# Generated by FakeRAM 2.0
VERSION 5.7 ;
BUSBITCHARS "[]" ;
PROPERTYDEFINITIONS
  MACRO width INTEGER ;
  MACRO depth INTEGER ;
  MACRO banks INTEGER ;
END PROPERTYDEFINITIONS
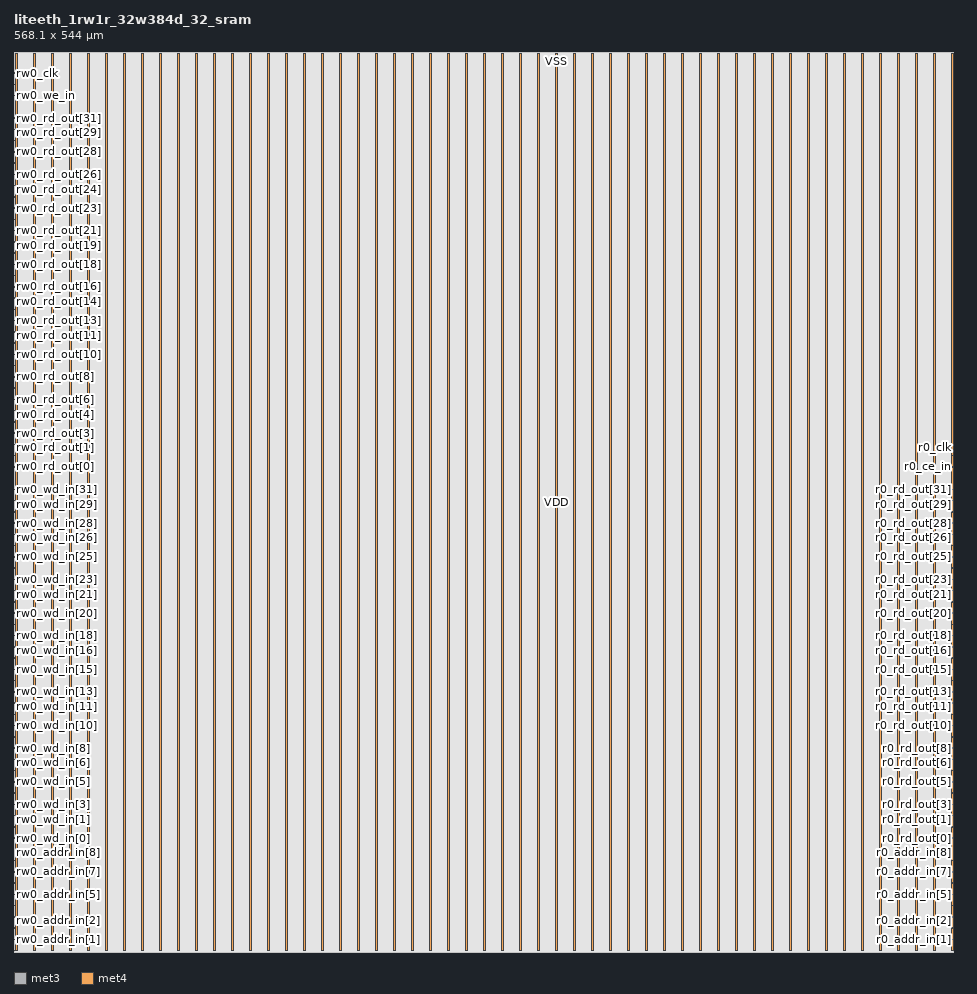
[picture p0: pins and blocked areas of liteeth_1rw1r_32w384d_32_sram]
MACRO liteeth_1rw1r_32w384d_32_sram
  PROPERTY width 32 ;
  PROPERTY depth 384 ;
  PROPERTY banks 1 ;
  FOREIGN liteeth_1rw1r_32w384d_32_sram 0 0 ;
  SYMMETRY X Y R90 ;
  SIZE 568.100 BY 544.000 ;
  CLASS BLOCK ;
  PIN r0_addr_in[0]
    DIRECTION INPUT ;
    USE SIGNAL ;
    SHAPE ABUTMENT ;
    PORT
      LAYER met3 ;
      RECT 567.300 0.680 568.100 0.980 ;
    END
  END r0_addr_in[0]
  PIN r0_addr_in[1]
    DIRECTION INPUT ;
    USE SIGNAL ;
    SHAPE ABUTMENT ;
    PORT
      LAYER met3 ;
      RECT 567.300 7.480 568.100 7.780 ;
    END
  END r0_addr_in[1]
  PIN r0_addr_in[2]
    DIRECTION INPUT ;
    USE SIGNAL ;
    SHAPE ABUTMENT ;
    PORT
      LAYER met3 ;
      RECT 567.300 14.280 568.100 14.580 ;
    END
  END r0_addr_in[2]
  PIN r0_addr_in[3]
    DIRECTION INPUT ;
    USE SIGNAL ;
    SHAPE ABUTMENT ;
    PORT
      LAYER met3 ;
      RECT 567.300 21.080 568.100 21.380 ;
    END
  END r0_addr_in[3]
  PIN r0_addr_in[4]
    DIRECTION INPUT ;
    USE SIGNAL ;
    SHAPE ABUTMENT ;
    PORT
      LAYER met3 ;
      RECT 567.300 27.880 568.100 28.180 ;
    END
  END r0_addr_in[4]
  PIN r0_addr_in[5]
    DIRECTION INPUT ;
    USE SIGNAL ;
    SHAPE ABUTMENT ;
    PORT
      LAYER met3 ;
      RECT 567.300 34.680 568.100 34.980 ;
    END
  END r0_addr_in[5]
  PIN r0_addr_in[6]
    DIRECTION INPUT ;
    USE SIGNAL ;
    SHAPE ABUTMENT ;
    PORT
      LAYER met3 ;
      RECT 567.300 41.480 568.100 41.780 ;
    END
  END r0_addr_in[6]
  PIN r0_addr_in[7]
    DIRECTION INPUT ;
    USE SIGNAL ;
    SHAPE ABUTMENT ;
    PORT
      LAYER met3 ;
      RECT 567.300 48.280 568.100 48.580 ;
    END
  END r0_addr_in[7]
  PIN r0_addr_in[8]
    DIRECTION INPUT ;
    USE SIGNAL ;
    SHAPE ABUTMENT ;
    PORT
      LAYER met3 ;
      RECT 567.300 55.080 568.100 55.380 ;
    END
  END r0_addr_in[8]
  PIN r0_rd_out[0]
    DIRECTION OUTPUT ;
    USE SIGNAL ;
    SHAPE ABUTMENT ;
    PORT
      LAYER met3 ;
      RECT 567.300 68.680 568.100 68.980 ;
    END
  END r0_rd_out[0]
  PIN r0_rd_out[1]
    DIRECTION OUTPUT ;
    USE SIGNAL ;
    SHAPE ABUTMENT ;
    PORT
      LAYER met3 ;
      RECT 567.300 75.480 568.100 75.780 ;
    END
  END r0_rd_out[1]
  PIN r0_rd_out[2]
    DIRECTION OUTPUT ;
    USE SIGNAL ;
    SHAPE ABUTMENT ;
    PORT
      LAYER met3 ;
      RECT 567.300 82.280 568.100 82.580 ;
    END
  END r0_rd_out[2]
  PIN r0_rd_out[3]
    DIRECTION OUTPUT ;
    USE SIGNAL ;
    SHAPE ABUTMENT ;
    PORT
      LAYER met3 ;
      RECT 567.300 89.080 568.100 89.380 ;
    END
  END r0_rd_out[3]
  PIN r0_rd_out[4]
    DIRECTION OUTPUT ;
    USE SIGNAL ;
    SHAPE ABUTMENT ;
    PORT
      LAYER met3 ;
      RECT 567.300 95.880 568.100 96.180 ;
    END
  END r0_rd_out[4]
  PIN r0_rd_out[5]
    DIRECTION OUTPUT ;
    USE SIGNAL ;
    SHAPE ABUTMENT ;
    PORT
      LAYER met3 ;
      RECT 567.300 102.680 568.100 102.980 ;
    END
  END r0_rd_out[5]
  PIN r0_rd_out[6]
    DIRECTION OUTPUT ;
    USE SIGNAL ;
    SHAPE ABUTMENT ;
    PORT
      LAYER met3 ;
      RECT 567.300 109.480 568.100 109.780 ;
    END
  END r0_rd_out[6]
  PIN r0_rd_out[7]
    DIRECTION OUTPUT ;
    USE SIGNAL ;
    SHAPE ABUTMENT ;
    PORT
      LAYER met3 ;
      RECT 567.300 116.280 568.100 116.580 ;
    END
  END r0_rd_out[7]
  PIN r0_rd_out[8]
    DIRECTION OUTPUT ;
    USE SIGNAL ;
    SHAPE ABUTMENT ;
    PORT
      LAYER met3 ;
      RECT 567.300 123.080 568.100 123.380 ;
    END
  END r0_rd_out[8]
  PIN r0_rd_out[9]
    DIRECTION OUTPUT ;
    USE SIGNAL ;
    SHAPE ABUTMENT ;
    PORT
      LAYER met3 ;
      RECT 567.300 129.880 568.100 130.180 ;
    END
  END r0_rd_out[9]
  PIN r0_rd_out[10]
    DIRECTION OUTPUT ;
    USE SIGNAL ;
    SHAPE ABUTMENT ;
    PORT
      LAYER met3 ;
      RECT 567.300 136.680 568.100 136.980 ;
    END
  END r0_rd_out[10]
  PIN r0_rd_out[11]
    DIRECTION OUTPUT ;
    USE SIGNAL ;
    SHAPE ABUTMENT ;
    PORT
      LAYER met3 ;
      RECT 567.300 143.480 568.100 143.780 ;
    END
  END r0_rd_out[11]
  PIN r0_rd_out[12]
    DIRECTION OUTPUT ;
    USE SIGNAL ;
    SHAPE ABUTMENT ;
    PORT
      LAYER met3 ;
      RECT 567.300 150.280 568.100 150.580 ;
    END
  END r0_rd_out[12]
  PIN r0_rd_out[13]
    DIRECTION OUTPUT ;
    USE SIGNAL ;
    SHAPE ABUTMENT ;
    PORT
      LAYER met3 ;
      RECT 567.300 157.080 568.100 157.380 ;
    END
  END r0_rd_out[13]
  PIN r0_rd_out[14]
    DIRECTION OUTPUT ;
    USE SIGNAL ;
    SHAPE ABUTMENT ;
    PORT
      LAYER met3 ;
      RECT 567.300 163.880 568.100 164.180 ;
    END
  END r0_rd_out[14]
  PIN r0_rd_out[15]
    DIRECTION OUTPUT ;
    USE SIGNAL ;
    SHAPE ABUTMENT ;
    PORT
      LAYER met3 ;
      RECT 567.300 170.680 568.100 170.980 ;
    END
  END r0_rd_out[15]
  PIN r0_rd_out[16]
    DIRECTION OUTPUT ;
    USE SIGNAL ;
    SHAPE ABUTMENT ;
    PORT
      LAYER met3 ;
      RECT 567.300 177.480 568.100 177.780 ;
    END
  END r0_rd_out[16]
  PIN r0_rd_out[17]
    DIRECTION OUTPUT ;
    USE SIGNAL ;
    SHAPE ABUTMENT ;
    PORT
      LAYER met3 ;
      RECT 567.300 184.280 568.100 184.580 ;
    END
  END r0_rd_out[17]
  PIN r0_rd_out[18]
    DIRECTION OUTPUT ;
    USE SIGNAL ;
    SHAPE ABUTMENT ;
    PORT
      LAYER met3 ;
      RECT 567.300 191.080 568.100 191.380 ;
    END
  END r0_rd_out[18]
  PIN r0_rd_out[19]
    DIRECTION OUTPUT ;
    USE SIGNAL ;
    SHAPE ABUTMENT ;
    PORT
      LAYER met3 ;
      RECT 567.300 197.880 568.100 198.180 ;
    END
  END r0_rd_out[19]
  PIN r0_rd_out[20]
    DIRECTION OUTPUT ;
    USE SIGNAL ;
    SHAPE ABUTMENT ;
    PORT
      LAYER met3 ;
      RECT 567.300 204.680 568.100 204.980 ;
    END
  END r0_rd_out[20]
  PIN r0_rd_out[21]
    DIRECTION OUTPUT ;
    USE SIGNAL ;
    SHAPE ABUTMENT ;
    PORT
      LAYER met3 ;
      RECT 567.300 211.480 568.100 211.780 ;
    END
  END r0_rd_out[21]
  PIN r0_rd_out[22]
    DIRECTION OUTPUT ;
    USE SIGNAL ;
    SHAPE ABUTMENT ;
    PORT
      LAYER met3 ;
      RECT 567.300 218.280 568.100 218.580 ;
    END
  END r0_rd_out[22]
  PIN r0_rd_out[23]
    DIRECTION OUTPUT ;
    USE SIGNAL ;
    SHAPE ABUTMENT ;
    PORT
      LAYER met3 ;
      RECT 567.300 225.080 568.100 225.380 ;
    END
  END r0_rd_out[23]
  PIN r0_rd_out[24]
    DIRECTION OUTPUT ;
    USE SIGNAL ;
    SHAPE ABUTMENT ;
    PORT
      LAYER met3 ;
      RECT 567.300 231.880 568.100 232.180 ;
    END
  END r0_rd_out[24]
  PIN r0_rd_out[25]
    DIRECTION OUTPUT ;
    USE SIGNAL ;
    SHAPE ABUTMENT ;
    PORT
      LAYER met3 ;
      RECT 567.300 238.680 568.100 238.980 ;
    END
  END r0_rd_out[25]
  PIN r0_rd_out[26]
    DIRECTION OUTPUT ;
    USE SIGNAL ;
    SHAPE ABUTMENT ;
    PORT
      LAYER met3 ;
      RECT 567.300 245.480 568.100 245.780 ;
    END
  END r0_rd_out[26]
  PIN r0_rd_out[27]
    DIRECTION OUTPUT ;
    USE SIGNAL ;
    SHAPE ABUTMENT ;
    PORT
      LAYER met3 ;
      RECT 567.300 252.280 568.100 252.580 ;
    END
  END r0_rd_out[27]
  PIN r0_rd_out[28]
    DIRECTION OUTPUT ;
    USE SIGNAL ;
    SHAPE ABUTMENT ;
    PORT
      LAYER met3 ;
      RECT 567.300 259.080 568.100 259.380 ;
    END
  END r0_rd_out[28]
  PIN r0_rd_out[29]
    DIRECTION OUTPUT ;
    USE SIGNAL ;
    SHAPE ABUTMENT ;
    PORT
      LAYER met3 ;
      RECT 567.300 265.880 568.100 266.180 ;
    END
  END r0_rd_out[29]
  PIN r0_rd_out[30]
    DIRECTION OUTPUT ;
    USE SIGNAL ;
    SHAPE ABUTMENT ;
    PORT
      LAYER met3 ;
      RECT 567.300 272.680 568.100 272.980 ;
    END
  END r0_rd_out[30]
  PIN r0_rd_out[31]
    DIRECTION OUTPUT ;
    USE SIGNAL ;
    SHAPE ABUTMENT ;
    PORT
      LAYER met3 ;
      RECT 567.300 279.480 568.100 279.780 ;
    END
  END r0_rd_out[31]
  PIN r0_ce_in
    DIRECTION INPUT ;
    USE SIGNAL ;
    SHAPE ABUTMENT ;
    PORT
      LAYER met3 ;
      RECT 567.300 293.080 568.100 293.380 ;
    END
  END r0_ce_in
  PIN r0_clk
    DIRECTION INPUT ;
    USE SIGNAL ;
    SHAPE ABUTMENT ;
    PORT
      LAYER met3 ;
      RECT 567.300 299.880 568.100 300.180 ;
    END
  END r0_clk
  PIN rw0_addr_in[0]
    DIRECTION INPUT ;
    USE SIGNAL ;
    SHAPE ABUTMENT ;
    PORT
      LAYER met3 ;
      RECT 0.000 0.680 0.800 0.980 ;
    END
  END rw0_addr_in[0]
  PIN rw0_addr_in[1]
    DIRECTION INPUT ;
    USE SIGNAL ;
    SHAPE ABUTMENT ;
    PORT
      LAYER met3 ;
      RECT 0.000 7.480 0.800 7.780 ;
    END
  END rw0_addr_in[1]
  PIN rw0_addr_in[2]
    DIRECTION INPUT ;
    USE SIGNAL ;
    SHAPE ABUTMENT ;
    PORT
      LAYER met3 ;
      RECT 0.000 14.280 0.800 14.580 ;
    END
  END rw0_addr_in[2]
  PIN rw0_addr_in[3]
    DIRECTION INPUT ;
    USE SIGNAL ;
    SHAPE ABUTMENT ;
    PORT
      LAYER met3 ;
      RECT 0.000 21.080 0.800 21.380 ;
    END
  END rw0_addr_in[3]
  PIN rw0_addr_in[4]
    DIRECTION INPUT ;
    USE SIGNAL ;
    SHAPE ABUTMENT ;
    PORT
      LAYER met3 ;
      RECT 0.000 27.880 0.800 28.180 ;
    END
  END rw0_addr_in[4]
  PIN rw0_addr_in[5]
    DIRECTION INPUT ;
    USE SIGNAL ;
    SHAPE ABUTMENT ;
    PORT
      LAYER met3 ;
      RECT 0.000 34.680 0.800 34.980 ;
    END
  END rw0_addr_in[5]
  PIN rw0_addr_in[6]
    DIRECTION INPUT ;
    USE SIGNAL ;
    SHAPE ABUTMENT ;
    PORT
      LAYER met3 ;
      RECT 0.000 41.480 0.800 41.780 ;
    END
  END rw0_addr_in[6]
  PIN rw0_addr_in[7]
    DIRECTION INPUT ;
    USE SIGNAL ;
    SHAPE ABUTMENT ;
    PORT
      LAYER met3 ;
      RECT 0.000 48.280 0.800 48.580 ;
    END
  END rw0_addr_in[7]
  PIN rw0_addr_in[8]
    DIRECTION INPUT ;
    USE SIGNAL ;
    SHAPE ABUTMENT ;
    PORT
      LAYER met3 ;
      RECT 0.000 55.080 0.800 55.380 ;
    END
  END rw0_addr_in[8]
  PIN rw0_wd_in[0]
    DIRECTION INPUT ;
    USE SIGNAL ;
    SHAPE ABUTMENT ;
    PORT
      LAYER met3 ;
      RECT 0.000 68.680 0.800 68.980 ;
    END
  END rw0_wd_in[0]
  PIN rw0_wd_in[1]
    DIRECTION INPUT ;
    USE SIGNAL ;
    SHAPE ABUTMENT ;
    PORT
      LAYER met3 ;
      RECT 0.000 75.480 0.800 75.780 ;
    END
  END rw0_wd_in[1]
  PIN rw0_wd_in[2]
    DIRECTION INPUT ;
    USE SIGNAL ;
    SHAPE ABUTMENT ;
    PORT
      LAYER met3 ;
      RECT 0.000 82.280 0.800 82.580 ;
    END
  END rw0_wd_in[2]
  PIN rw0_wd_in[3]
    DIRECTION INPUT ;
    USE SIGNAL ;
    SHAPE ABUTMENT ;
    PORT
      LAYER met3 ;
      RECT 0.000 89.080 0.800 89.380 ;
    END
  END rw0_wd_in[3]
  PIN rw0_wd_in[4]
    DIRECTION INPUT ;
    USE SIGNAL ;
    SHAPE ABUTMENT ;
    PORT
      LAYER met3 ;
      RECT 0.000 95.880 0.800 96.180 ;
    END
  END rw0_wd_in[4]
  PIN rw0_wd_in[5]
    DIRECTION INPUT ;
    USE SIGNAL ;
    SHAPE ABUTMENT ;
    PORT
      LAYER met3 ;
      RECT 0.000 102.680 0.800 102.980 ;
    END
  END rw0_wd_in[5]
  PIN rw0_wd_in[6]
    DIRECTION INPUT ;
    USE SIGNAL ;
    SHAPE ABUTMENT ;
    PORT
      LAYER met3 ;
      RECT 0.000 109.480 0.800 109.780 ;
    END
  END rw0_wd_in[6]
  PIN rw0_wd_in[7]
    DIRECTION INPUT ;
    USE SIGNAL ;
    SHAPE ABUTMENT ;
    PORT
      LAYER met3 ;
      RECT 0.000 116.280 0.800 116.580 ;
    END
  END rw0_wd_in[7]
  PIN rw0_wd_in[8]
    DIRECTION INPUT ;
    USE SIGNAL ;
    SHAPE ABUTMENT ;
    PORT
      LAYER met3 ;
      RECT 0.000 123.080 0.800 123.380 ;
    END
  END rw0_wd_in[8]
  PIN rw0_wd_in[9]
    DIRECTION INPUT ;
    USE SIGNAL ;
    SHAPE ABUTMENT ;
    PORT
      LAYER met3 ;
      RECT 0.000 129.880 0.800 130.180 ;
    END
  END rw0_wd_in[9]
  PIN rw0_wd_in[10]
    DIRECTION INPUT ;
    USE SIGNAL ;
    SHAPE ABUTMENT ;
    PORT
      LAYER met3 ;
      RECT 0.000 136.680 0.800 136.980 ;
    END
  END rw0_wd_in[10]
  PIN rw0_wd_in[11]
    DIRECTION INPUT ;
    USE SIGNAL ;
    SHAPE ABUTMENT ;
    PORT
      LAYER met3 ;
      RECT 0.000 143.480 0.800 143.780 ;
    END
  END rw0_wd_in[11]
  PIN rw0_wd_in[12]
    DIRECTION INPUT ;
    USE SIGNAL ;
    SHAPE ABUTMENT ;
    PORT
      LAYER met3 ;
      RECT 0.000 150.280 0.800 150.580 ;
    END
  END rw0_wd_in[12]
  PIN rw0_wd_in[13]
    DIRECTION INPUT ;
    USE SIGNAL ;
    SHAPE ABUTMENT ;
    PORT
      LAYER met3 ;
      RECT 0.000 157.080 0.800 157.380 ;
    END
  END rw0_wd_in[13]
  PIN rw0_wd_in[14]
    DIRECTION INPUT ;
    USE SIGNAL ;
    SHAPE ABUTMENT ;
    PORT
      LAYER met3 ;
      RECT 0.000 163.880 0.800 164.180 ;
    END
  END rw0_wd_in[14]
  PIN rw0_wd_in[15]
    DIRECTION INPUT ;
    USE SIGNAL ;
    SHAPE ABUTMENT ;
    PORT
      LAYER met3 ;
      RECT 0.000 170.680 0.800 170.980 ;
    END
  END rw0_wd_in[15]
  PIN rw0_wd_in[16]
    DIRECTION INPUT ;
    USE SIGNAL ;
    SHAPE ABUTMENT ;
    PORT
      LAYER met3 ;
      RECT 0.000 177.480 0.800 177.780 ;
    END
  END rw0_wd_in[16]
  PIN rw0_wd_in[17]
    DIRECTION INPUT ;
    USE SIGNAL ;
    SHAPE ABUTMENT ;
    PORT
      LAYER met3 ;
      RECT 0.000 184.280 0.800 184.580 ;
    END
  END rw0_wd_in[17]
  PIN rw0_wd_in[18]
    DIRECTION INPUT ;
    USE SIGNAL ;
    SHAPE ABUTMENT ;
    PORT
      LAYER met3 ;
      RECT 0.000 191.080 0.800 191.380 ;
    END
  END rw0_wd_in[18]
  PIN rw0_wd_in[19]
    DIRECTION INPUT ;
    USE SIGNAL ;
    SHAPE ABUTMENT ;
    PORT
      LAYER met3 ;
      RECT 0.000 197.880 0.800 198.180 ;
    END
  END rw0_wd_in[19]
  PIN rw0_wd_in[20]
    DIRECTION INPUT ;
    USE SIGNAL ;
    SHAPE ABUTMENT ;
    PORT
      LAYER met3 ;
      RECT 0.000 204.680 0.800 204.980 ;
    END
  END rw0_wd_in[20]
  PIN rw0_wd_in[21]
    DIRECTION INPUT ;
    USE SIGNAL ;
    SHAPE ABUTMENT ;
    PORT
      LAYER met3 ;
      RECT 0.000 211.480 0.800 211.780 ;
    END
  END rw0_wd_in[21]
  PIN rw0_wd_in[22]
    DIRECTION INPUT ;
    USE SIGNAL ;
    SHAPE ABUTMENT ;
    PORT
      LAYER met3 ;
      RECT 0.000 218.280 0.800 218.580 ;
    END
  END rw0_wd_in[22]
  PIN rw0_wd_in[23]
    DIRECTION INPUT ;
    USE SIGNAL ;
    SHAPE ABUTMENT ;
    PORT
      LAYER met3 ;
      RECT 0.000 225.080 0.800 225.380 ;
    END
  END rw0_wd_in[23]
  PIN rw0_wd_in[24]
    DIRECTION INPUT ;
    USE SIGNAL ;
    SHAPE ABUTMENT ;
    PORT
      LAYER met3 ;
      RECT 0.000 231.880 0.800 232.180 ;
    END
  END rw0_wd_in[24]
  PIN rw0_wd_in[25]
    DIRECTION INPUT ;
    USE SIGNAL ;
    SHAPE ABUTMENT ;
    PORT
      LAYER met3 ;
      RECT 0.000 238.680 0.800 238.980 ;
    END
  END rw0_wd_in[25]
  PIN rw0_wd_in[26]
    DIRECTION INPUT ;
    USE SIGNAL ;
    SHAPE ABUTMENT ;
    PORT
      LAYER met3 ;
      RECT 0.000 245.480 0.800 245.780 ;
    END
  END rw0_wd_in[26]
  PIN rw0_wd_in[27]
    DIRECTION INPUT ;
    USE SIGNAL ;
    SHAPE ABUTMENT ;
    PORT
      LAYER met3 ;
      RECT 0.000 252.280 0.800 252.580 ;
    END
  END rw0_wd_in[27]
  PIN rw0_wd_in[28]
    DIRECTION INPUT ;
    USE SIGNAL ;
    SHAPE ABUTMENT ;
    PORT
      LAYER met3 ;
      RECT 0.000 259.080 0.800 259.380 ;
    END
  END rw0_wd_in[28]
  PIN rw0_wd_in[29]
    DIRECTION INPUT ;
    USE SIGNAL ;
    SHAPE ABUTMENT ;
    PORT
      LAYER met3 ;
      RECT 0.000 265.880 0.800 266.180 ;
    END
  END rw0_wd_in[29]
  PIN rw0_wd_in[30]
    DIRECTION INPUT ;
    USE SIGNAL ;
    SHAPE ABUTMENT ;
    PORT
      LAYER met3 ;
      RECT 0.000 272.680 0.800 272.980 ;
    END
  END rw0_wd_in[30]
  PIN rw0_wd_in[31]
    DIRECTION INPUT ;
    USE SIGNAL ;
    SHAPE ABUTMENT ;
    PORT
      LAYER met3 ;
      RECT 0.000 279.480 0.800 279.780 ;
    END
  END rw0_wd_in[31]
  PIN rw0_rd_out[0]
    DIRECTION OUTPUT ;
    USE SIGNAL ;
    SHAPE ABUTMENT ;
    PORT
      LAYER met3 ;
      RECT 0.000 293.080 0.800 293.380 ;
    END
  END rw0_rd_out[0]
  PIN rw0_rd_out[1]
    DIRECTION OUTPUT ;
    USE SIGNAL ;
    SHAPE ABUTMENT ;
    PORT
      LAYER met3 ;
      RECT 0.000 299.880 0.800 300.180 ;
    END
  END rw0_rd_out[1]
  PIN rw0_rd_out[2]
    DIRECTION OUTPUT ;
    USE SIGNAL ;
    SHAPE ABUTMENT ;
    PORT
      LAYER met3 ;
      RECT 0.000 306.680 0.800 306.980 ;
    END
  END rw0_rd_out[2]
  PIN rw0_rd_out[3]
    DIRECTION OUTPUT ;
    USE SIGNAL ;
    SHAPE ABUTMENT ;
    PORT
      LAYER met3 ;
      RECT 0.000 313.480 0.800 313.780 ;
    END
  END rw0_rd_out[3]
  PIN rw0_rd_out[4]
    DIRECTION OUTPUT ;
    USE SIGNAL ;
    SHAPE ABUTMENT ;
    PORT
      LAYER met3 ;
      RECT 0.000 320.280 0.800 320.580 ;
    END
  END rw0_rd_out[4]
  PIN rw0_rd_out[5]
    DIRECTION OUTPUT ;
    USE SIGNAL ;
    SHAPE ABUTMENT ;
    PORT
      LAYER met3 ;
      RECT 0.000 327.080 0.800 327.380 ;
    END
  END rw0_rd_out[5]
  PIN rw0_rd_out[6]
    DIRECTION OUTPUT ;
    USE SIGNAL ;
    SHAPE ABUTMENT ;
    PORT
      LAYER met3 ;
      RECT 0.000 333.880 0.800 334.180 ;
    END
  END rw0_rd_out[6]
  PIN rw0_rd_out[7]
    DIRECTION OUTPUT ;
    USE SIGNAL ;
    SHAPE ABUTMENT ;
    PORT
      LAYER met3 ;
      RECT 0.000 340.680 0.800 340.980 ;
    END
  END rw0_rd_out[7]
  PIN rw0_rd_out[8]
    DIRECTION OUTPUT ;
    USE SIGNAL ;
    SHAPE ABUTMENT ;
    PORT
      LAYER met3 ;
      RECT 0.000 347.480 0.800 347.780 ;
    END
  END rw0_rd_out[8]
  PIN rw0_rd_out[9]
    DIRECTION OUTPUT ;
    USE SIGNAL ;
    SHAPE ABUTMENT ;
    PORT
      LAYER met3 ;
      RECT 0.000 354.280 0.800 354.580 ;
    END
  END rw0_rd_out[9]
  PIN rw0_rd_out[10]
    DIRECTION OUTPUT ;
    USE SIGNAL ;
    SHAPE ABUTMENT ;
    PORT
      LAYER met3 ;
      RECT 0.000 361.080 0.800 361.380 ;
    END
  END rw0_rd_out[10]
  PIN rw0_rd_out[11]
    DIRECTION OUTPUT ;
    USE SIGNAL ;
    SHAPE ABUTMENT ;
    PORT
      LAYER met3 ;
      RECT 0.000 367.880 0.800 368.180 ;
    END
  END rw0_rd_out[11]
  PIN rw0_rd_out[12]
    DIRECTION OUTPUT ;
    USE SIGNAL ;
    SHAPE ABUTMENT ;
    PORT
      LAYER met3 ;
      RECT 0.000 374.680 0.800 374.980 ;
    END
  END rw0_rd_out[12]
  PIN rw0_rd_out[13]
    DIRECTION OUTPUT ;
    USE SIGNAL ;
    SHAPE ABUTMENT ;
    PORT
      LAYER met3 ;
      RECT 0.000 381.480 0.800 381.780 ;
    END
  END rw0_rd_out[13]
  PIN rw0_rd_out[14]
    DIRECTION OUTPUT ;
    USE SIGNAL ;
    SHAPE ABUTMENT ;
    PORT
      LAYER met3 ;
      RECT 0.000 388.280 0.800 388.580 ;
    END
  END rw0_rd_out[14]
  PIN rw0_rd_out[15]
    DIRECTION OUTPUT ;
    USE SIGNAL ;
    SHAPE ABUTMENT ;
    PORT
      LAYER met3 ;
      RECT 0.000 395.080 0.800 395.380 ;
    END
  END rw0_rd_out[15]
  PIN rw0_rd_out[16]
    DIRECTION OUTPUT ;
    USE SIGNAL ;
    SHAPE ABUTMENT ;
    PORT
      LAYER met3 ;
      RECT 0.000 401.880 0.800 402.180 ;
    END
  END rw0_rd_out[16]
  PIN rw0_rd_out[17]
    DIRECTION OUTPUT ;
    USE SIGNAL ;
    SHAPE ABUTMENT ;
    PORT
      LAYER met3 ;
      RECT 0.000 408.680 0.800 408.980 ;
    END
  END rw0_rd_out[17]
  PIN rw0_rd_out[18]
    DIRECTION OUTPUT ;
    USE SIGNAL ;
    SHAPE ABUTMENT ;
    PORT
      LAYER met3 ;
      RECT 0.000 415.480 0.800 415.780 ;
    END
  END rw0_rd_out[18]
  PIN rw0_rd_out[19]
    DIRECTION OUTPUT ;
    USE SIGNAL ;
    SHAPE ABUTMENT ;
    PORT
      LAYER met3 ;
      RECT 0.000 422.280 0.800 422.580 ;
    END
  END rw0_rd_out[19]
  PIN rw0_rd_out[20]
    DIRECTION OUTPUT ;
    USE SIGNAL ;
    SHAPE ABUTMENT ;
    PORT
      LAYER met3 ;
      RECT 0.000 429.080 0.800 429.380 ;
    END
  END rw0_rd_out[20]
  PIN rw0_rd_out[21]
    DIRECTION OUTPUT ;
    USE SIGNAL ;
    SHAPE ABUTMENT ;
    PORT
      LAYER met3 ;
      RECT 0.000 435.880 0.800 436.180 ;
    END
  END rw0_rd_out[21]
  PIN rw0_rd_out[22]
    DIRECTION OUTPUT ;
    USE SIGNAL ;
    SHAPE ABUTMENT ;
    PORT
      LAYER met3 ;
      RECT 0.000 442.680 0.800 442.980 ;
    END
  END rw0_rd_out[22]
  PIN rw0_rd_out[23]
    DIRECTION OUTPUT ;
    USE SIGNAL ;
    SHAPE ABUTMENT ;
    PORT
      LAYER met3 ;
      RECT 0.000 449.480 0.800 449.780 ;
    END
  END rw0_rd_out[23]
  PIN rw0_rd_out[24]
    DIRECTION OUTPUT ;
    USE SIGNAL ;
    SHAPE ABUTMENT ;
    PORT
      LAYER met3 ;
      RECT 0.000 456.280 0.800 456.580 ;
    END
  END rw0_rd_out[24]
  PIN rw0_rd_out[25]
    DIRECTION OUTPUT ;
    USE SIGNAL ;
    SHAPE ABUTMENT ;
    PORT
      LAYER met3 ;
      RECT 0.000 463.080 0.800 463.380 ;
    END
  END rw0_rd_out[25]
  PIN rw0_rd_out[26]
    DIRECTION OUTPUT ;
    USE SIGNAL ;
    SHAPE ABUTMENT ;
    PORT
      LAYER met3 ;
      RECT 0.000 469.880 0.800 470.180 ;
    END
  END rw0_rd_out[26]
  PIN rw0_rd_out[27]
    DIRECTION OUTPUT ;
    USE SIGNAL ;
    SHAPE ABUTMENT ;
    PORT
      LAYER met3 ;
      RECT 0.000 476.680 0.800 476.980 ;
    END
  END rw0_rd_out[27]
  PIN rw0_rd_out[28]
    DIRECTION OUTPUT ;
    USE SIGNAL ;
    SHAPE ABUTMENT ;
    PORT
      LAYER met3 ;
      RECT 0.000 483.480 0.800 483.780 ;
    END
  END rw0_rd_out[28]
  PIN rw0_rd_out[29]
    DIRECTION OUTPUT ;
    USE SIGNAL ;
    SHAPE ABUTMENT ;
    PORT
      LAYER met3 ;
      RECT 0.000 490.280 0.800 490.580 ;
    END
  END rw0_rd_out[29]
  PIN rw0_rd_out[30]
    DIRECTION OUTPUT ;
    USE SIGNAL ;
    SHAPE ABUTMENT ;
    PORT
      LAYER met3 ;
      RECT 0.000 497.080 0.800 497.380 ;
    END
  END rw0_rd_out[30]
  PIN rw0_rd_out[31]
    DIRECTION OUTPUT ;
    USE SIGNAL ;
    SHAPE ABUTMENT ;
    PORT
      LAYER met3 ;
      RECT 0.000 503.880 0.800 504.180 ;
    END
  END rw0_rd_out[31]
  PIN rw0_we_in
    DIRECTION INPUT ;
    USE SIGNAL ;
    SHAPE ABUTMENT ;
    PORT
      LAYER met3 ;
      RECT 0.000 517.480 0.800 517.780 ;
    END
  END rw0_we_in
  PIN rw0_ce_in
    DIRECTION INPUT ;
    USE SIGNAL ;
    SHAPE ABUTMENT ;
    PORT
      LAYER met3 ;
      RECT 0.000 524.280 0.800 524.580 ;
    END
  END rw0_ce_in
  PIN rw0_clk
    DIRECTION INPUT ;
    USE SIGNAL ;
    SHAPE ABUTMENT ;
    PORT
      LAYER met3 ;
      RECT 0.000 531.080 0.800 531.380 ;
    END
  END rw0_clk
  PIN VSS
    DIRECTION INOUT ;
    USE GROUND ;
    PORT
      LAYER met4 ;
      RECT 1.060 0.680 2.260 543.320 ;
      RECT 11.940 0.680 13.140 543.320 ;
      RECT 22.820 0.680 24.020 543.320 ;
      RECT 33.700 0.680 34.900 543.320 ;
      RECT 44.580 0.680 45.780 543.320 ;
      RECT 55.460 0.680 56.660 543.320 ;
      RECT 66.340 0.680 67.540 543.320 ;
      RECT 77.220 0.680 78.420 543.320 ;
      RECT 88.100 0.680 89.300 543.320 ;
      RECT 98.980 0.680 100.180 543.320 ;
      RECT 109.860 0.680 111.060 543.320 ;
      RECT 120.740 0.680 121.940 543.320 ;
      RECT 131.620 0.680 132.820 543.320 ;
      RECT 142.500 0.680 143.700 543.320 ;
      RECT 153.380 0.680 154.580 543.320 ;
      RECT 164.260 0.680 165.460 543.320 ;
      RECT 175.140 0.680 176.340 543.320 ;
      RECT 186.020 0.680 187.220 543.320 ;
      RECT 196.900 0.680 198.100 543.320 ;
      RECT 207.780 0.680 208.980 543.320 ;
      RECT 218.660 0.680 219.860 543.320 ;
      RECT 229.540 0.680 230.740 543.320 ;
      RECT 240.420 0.680 241.620 543.320 ;
      RECT 251.300 0.680 252.500 543.320 ;
      RECT 262.180 0.680 263.380 543.320 ;
      RECT 273.060 0.680 274.260 543.320 ;
      RECT 283.940 0.680 285.140 543.320 ;
      RECT 294.820 0.680 296.020 543.320 ;
      RECT 305.700 0.680 306.900 543.320 ;
      RECT 316.580 0.680 317.780 543.320 ;
      RECT 327.460 0.680 328.660 543.320 ;
      RECT 338.340 0.680 339.540 543.320 ;
      RECT 349.220 0.680 350.420 543.320 ;
      RECT 360.100 0.680 361.300 543.320 ;
      RECT 370.980 0.680 372.180 543.320 ;
      RECT 381.860 0.680 383.060 543.320 ;
      RECT 392.740 0.680 393.940 543.320 ;
      RECT 403.620 0.680 404.820 543.320 ;
      RECT 414.500 0.680 415.700 543.320 ;
      RECT 425.380 0.680 426.580 543.320 ;
      RECT 436.260 0.680 437.460 543.320 ;
      RECT 447.140 0.680 448.340 543.320 ;
      RECT 458.020 0.680 459.220 543.320 ;
      RECT 468.900 0.680 470.100 543.320 ;
      RECT 479.780 0.680 480.980 543.320 ;
      RECT 490.660 0.680 491.860 543.320 ;
      RECT 501.540 0.680 502.740 543.320 ;
      RECT 512.420 0.680 513.620 543.320 ;
      RECT 523.300 0.680 524.500 543.320 ;
      RECT 534.180 0.680 535.380 543.320 ;
      RECT 545.060 0.680 546.260 543.320 ;
      RECT 555.940 0.680 557.140 543.320 ;
      RECT 566.820 0.680 568.020 543.320 ;
    END
  END VSS
  PIN VDD
    DIRECTION INOUT ;
    USE POWER ;
    PORT
      LAYER met4 ;
      RECT 1.060 0.680 2.260 543.320 ;
      RECT 11.940 0.680 13.140 543.320 ;
      RECT 22.820 0.680 24.020 543.320 ;
      RECT 33.700 0.680 34.900 543.320 ;
      RECT 44.580 0.680 45.780 543.320 ;
      RECT 55.460 0.680 56.660 543.320 ;
      RECT 66.340 0.680 67.540 543.320 ;
      RECT 77.220 0.680 78.420 543.320 ;
      RECT 88.100 0.680 89.300 543.320 ;
      RECT 98.980 0.680 100.180 543.320 ;
      RECT 109.860 0.680 111.060 543.320 ;
      RECT 120.740 0.680 121.940 543.320 ;
      RECT 131.620 0.680 132.820 543.320 ;
      RECT 142.500 0.680 143.700 543.320 ;
      RECT 153.380 0.680 154.580 543.320 ;
      RECT 164.260 0.680 165.460 543.320 ;
      RECT 175.140 0.680 176.340 543.320 ;
      RECT 186.020 0.680 187.220 543.320 ;
      RECT 196.900 0.680 198.100 543.320 ;
      RECT 207.780 0.680 208.980 543.320 ;
      RECT 218.660 0.680 219.860 543.320 ;
      RECT 229.540 0.680 230.740 543.320 ;
      RECT 240.420 0.680 241.620 543.320 ;
      RECT 251.300 0.680 252.500 543.320 ;
      RECT 262.180 0.680 263.380 543.320 ;
      RECT 273.060 0.680 274.260 543.320 ;
      RECT 283.940 0.680 285.140 543.320 ;
      RECT 294.820 0.680 296.020 543.320 ;
      RECT 305.700 0.680 306.900 543.320 ;
      RECT 316.580 0.680 317.780 543.320 ;
      RECT 327.460 0.680 328.660 543.320 ;
      RECT 338.340 0.680 339.540 543.320 ;
      RECT 349.220 0.680 350.420 543.320 ;
      RECT 360.100 0.680 361.300 543.320 ;
      RECT 370.980 0.680 372.180 543.320 ;
      RECT 381.860 0.680 383.060 543.320 ;
      RECT 392.740 0.680 393.940 543.320 ;
      RECT 403.620 0.680 404.820 543.320 ;
      RECT 414.500 0.680 415.700 543.320 ;
      RECT 425.380 0.680 426.580 543.320 ;
      RECT 436.260 0.680 437.460 543.320 ;
      RECT 447.140 0.680 448.340 543.320 ;
      RECT 458.020 0.680 459.220 543.320 ;
      RECT 468.900 0.680 470.100 543.320 ;
      RECT 479.780 0.680 480.980 543.320 ;
      RECT 490.660 0.680 491.860 543.320 ;
      RECT 501.540 0.680 502.740 543.320 ;
      RECT 512.420 0.680 513.620 543.320 ;
      RECT 523.300 0.680 524.500 543.320 ;
      RECT 534.180 0.680 535.380 543.320 ;
      RECT 545.060 0.680 546.260 543.320 ;
      RECT 555.940 0.680 557.140 543.320 ;
      RECT 566.820 0.680 568.020 543.320 ;
    END
  END VDD
  OBS
    LAYER met1 ;
    RECT 0 0 568.100 544.000 ;
    LAYER met2 ;
    RECT 0 0 568.100 544.000 ;
    LAYER met3 ;
    RECT 0 0 568.100 544.000 ;
    LAYER met4 ;
    RECT 0 0 568.100 544.000 ;
    LAYER OVERLAP ;
    RECT 0 0 568.100 544.000 ;
  END
END liteeth_1rw1r_32w384d_32_sram

END LIBRARY
